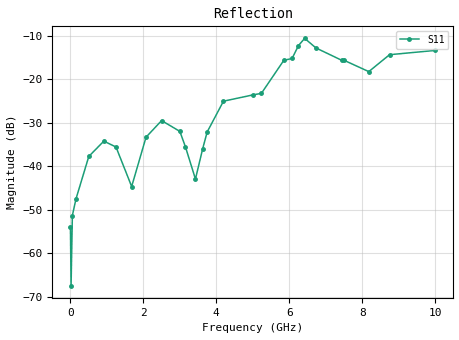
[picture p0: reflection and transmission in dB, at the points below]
! 2/19/2018 12:52:16 PM
! E:\STEPPED_EXPERIMENT_2018-02-19\P1-MSL_LOAD_50.S1P
! CHANNEL.1
! TR.MEASUREMENT
! CORRECTED.DATA
# GHZ S RI R 50.0
! FREQ.GHZ  S11RE  S11IM
!; PortSelection: Port_1
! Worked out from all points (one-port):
!   10000 points, 1 MHz to 10 GHz, reference 50 ohm
!   lowest |S11| = -67.5 dB at 19 MHz (marker M1), VSWR 1.00, Z = 50 - j0.042 ohm
!   |S11| at or under -10 dB: start of sweep to 6.381 GHz; 6.406 GHz to 6.454 GHz (47.5 MHz wide, 0.739 % of centre); 6.46 GHz to end of sweep
!   S11 on the Smith chart (normalised r, x): 1 MHz: 1.00, -0.00; 6.079 GHz: 0.79, +0.23; 6.732 GHz: 1.54, +0.21; 7.436 GHz: 1.15, -0.33; 10 GHz: 0.65, -0.02
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0.001  0.000994 -0.00173
0.019  3.75e-05 -0.00042
0.054  -0.00115 -0.00244
0.154  -0.00291 -0.00303
0.505  -0.0118 0.00524
0.917  -0.00131 0.0193
1.251  0.0115 0.0119
1.68  0.00236 0.00532
2.074  0.0049 0.0209
2.501  0.0293 0.0159
3.001  0.019 -0.0163
3.156  0.00836 -0.0143
3.429  0.00649 -0.00285
3.627  0.0143 0.00673
3.751  0.024 0.00575
4.197  0.0346 -0.0436
5.001  -0.0554 -0.0353
5.238  -0.064 -0.0246
5.852  -0.1467 0.0738
6.079  -0.0967 0.1427
6.251  -0.0944 0.2226
6.423  0.081 0.2822
6.732  0.2189 0.0639
7.436  0.0894 -0.1382
7.501  0.0729 -0.1475
8.182  -0.0316 -0.1176
8.751  -0.1065 -0.158
10  -0.2128 -0.0138
